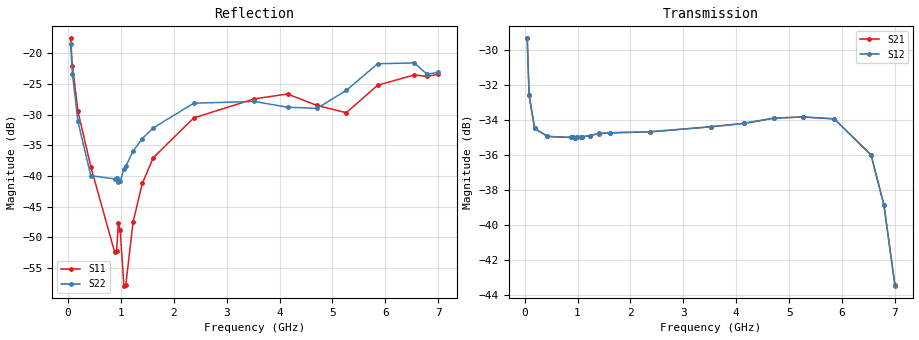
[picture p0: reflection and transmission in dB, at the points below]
! Integrated Device Technology
! Corporate Headquarters
! 6024 Silver Creek Valley Road
! San Jose, CA 95138  USA
! Phone:  1-408-284-8200
! Toll Free:  1-800-223-1366
! Webpage:  http://www.idt.com/
! Timing and RF Division
! 515 Groton Road, Suite 102
! Westford, MA 01886-6024
! Device:  F2258
! Description: Voltage Variable RF Attenuator
! Frequency:  50.0 -  6000.00 MHz
! Package:  3x3 mm Thin QFN Plastic Package: 16 pin
! Ports:  2 RF, 2 DC
!  Pin  1  = NC
!  Pin  2  = NC
!  Pin  3  = RF2  = Port 2
!  Pin  4  = GND
!  Pin  5  = Vdd
!  Pin  6  = NC
!  Pin  7  = VCTRL
!  Pin  8  = NC
!  Pin  9  = GND
!  Pin 10  = RF1  = Port 1
!  Pin 11  = NC
!  Pin 12  = NC
!  Pin 13  = NC
!  Pin 14  = NC
!  Pin 15  = NC
!  Pin 16  = NC
! Vcntrl:  2.010 Volts
! Vdd:  +3.300 Volts
! Current:  1.155 mA
! Data:  The device was measured on a the F2258 evaluation board which has
!  individual transmission lines to the RF pins.  Data was collected
!  using a calibrated network analyzer.  The evaluation board was
!  de-embedded using a TRL calibration technique.
!  The reference plane is the edge of the package pin.
! Misc:  SN 10
!  Action Tracker AT0285
! Date Measured:  2014-12-10
! Date:  2016-01-13  MJV
! Note:
!  Integrated Device Technology supplies this data as a sample of measured
!  data at the package pin for this product.  Your particular data for this
!  product may vary.
!  Data was taken at 25 degrees C.
!  Integrated Device Technology reserves the right to change this data at anytime.
!Freq_(GHz)  S11M_(dB)  S11P_(deg)  S21M_(dB)  S21P_(deg)  S12M_(dB)  S12P_(deg)  S22M_(dB)  S22P_(deg)
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# GHz S dB R 50
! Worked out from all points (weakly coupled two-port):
!   201 points, 50 MHz to 7 GHz, reference 50 ohm
!   highest |S21| = -29.36 dB at 50 MHz (marker M1); lowest = -43.4 dB at 7 GHz (marker M2)
!   lowest |S11| = -57.9 dB at 1.058 GHz (marker M3), VSWR 1.00, Z = 49.9 + j0.0519 ohm
!   |S11| at or under -10 dB: start of sweep to end of sweep
!   |S22| runs from -41.1 to -18.4 dB; largest |S21 - S12| = 7.8e-05
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0.05  -17.55 -110.9  -29.36 -66.7  -29.36 -66.8  -18.44 -108.3
0.08475  -21.98 -107.4  -32.58 -47.2  -32.58 -47.2  -23.29 -99.6
0.189  -29.43 -109.3  -34.49 -24.0  -34.49 -24.0  -31.10 -86.7
0.43225  -38.46 -119.3  -34.95 -12.3  -34.95 -12.3  -39.93 -43.9
0.884  -52.45 166.6  -35.01 -8.6  -35.01 -8.6  -40.46 20.2
0.91875  -52.24 149.9  -35.01 -8.6  -35.01 -8.6  -40.27 21.9
0.9535  -47.63 -161.8  -35.02 -8.5  -35.02 -8.5  -41.01 42.8
0.98825  -48.86 -173.6  -35.01 -8.4  -35.00 -8.4  -40.86 39.2
1.05775  -57.87 156.0  -34.99 -8.3  -34.99 -8.3  -38.88 35.6
1.0925  -57.82 117.1  -34.98 -8.3  -34.97 -8.3  -38.43 34.8
1.2315  -47.47 46.0  -34.90 -8.3  -34.90 -8.3  -35.95 29.7
1.40525  -41.20 33.6  -34.79 -9.0  -34.78 -9.0  -33.89 29.3
1.61375  -36.99 32.5  -34.75 -10.2  -34.74 -10.2  -32.15 24.8
2.37825  -30.52 48.1  -34.69 -14.0  -34.68 -14.0  -28.12 25.8
3.525  -27.41 91.6  -34.40 -20.7  -34.40 -20.7  -27.84 52.9
4.1505  -26.62 104.9  -34.20 -25.2  -34.21 -25.3  -28.77 62.8
4.7065  -28.48 95.6  -33.91 -30.0  -33.91 -30.0  -28.96 44.4
5.2625  -29.67 54.3  -33.84 -36.1  -33.84 -36.1  -26.03 8.2
5.85325  -25.19 29.8  -33.95 -46.5  -33.95 -46.5  -21.69 -10.4
6.54825  -23.51 45.0  -36.00 -66.7  -36.01 -66.7  -21.55 -44.1
6.7915  -23.76 63.2  -38.84 -73.2  -38.88 -73.0  -23.43 -78.3
7  -23.38 84.4  -43.44 -62.3  -43.46 -62.0  -23.04 -127.9
